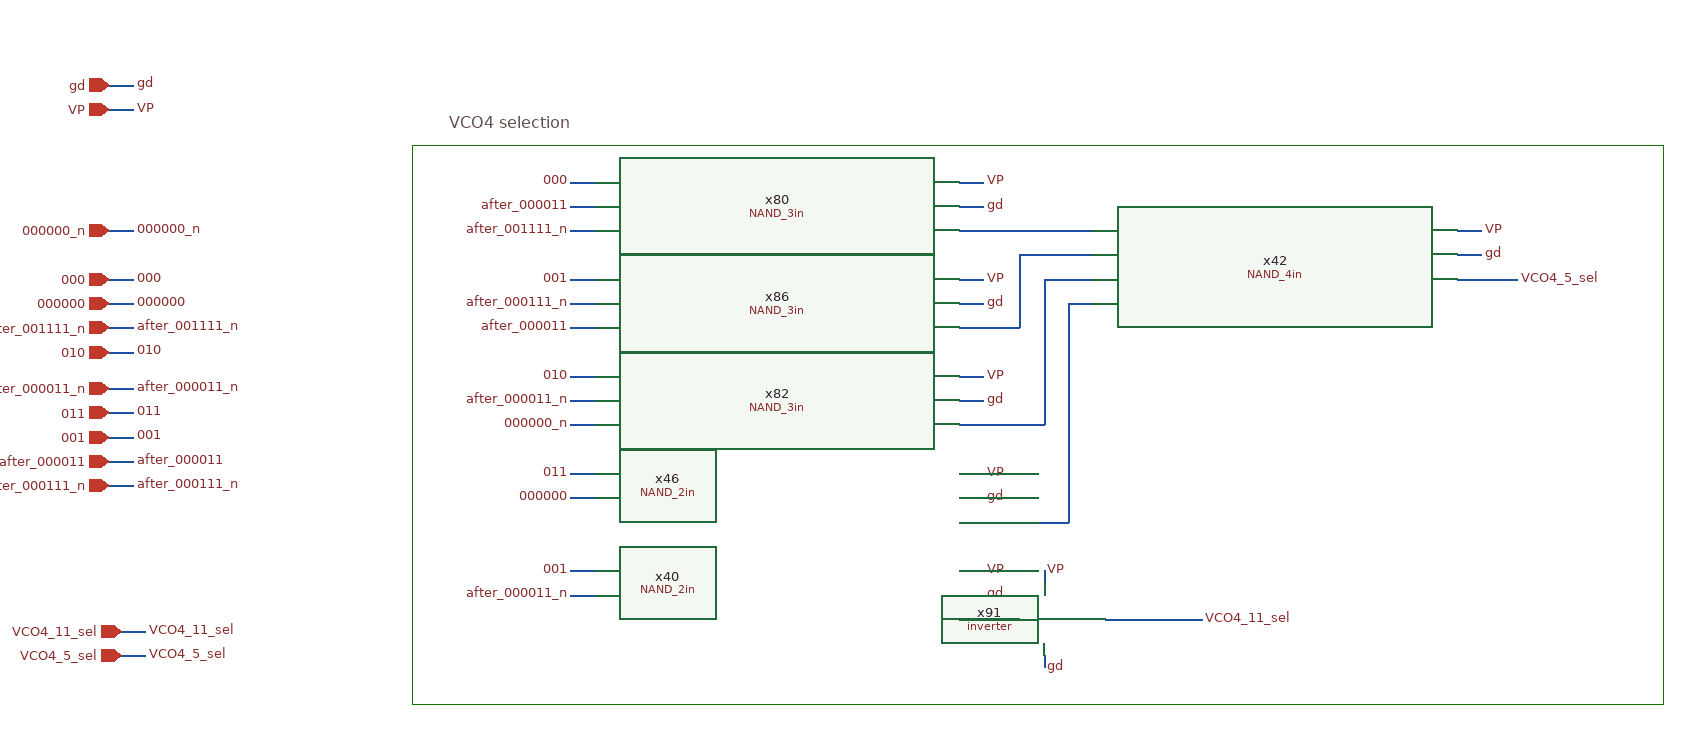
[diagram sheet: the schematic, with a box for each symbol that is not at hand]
v {xschem version=3.4.8RC file_version=1.3}
G {}
K {}
V {}
S {}
F {}
E {}
L 4 2020 -2830 2020 -2490 {}
L 4 2190 -2830 2530 -2830 {}
L 4 2510 -2830 2850 -2830 {}
L 4 2220 -2830 2560 -2830 {}
L 4 2560 -2830 2900 -2830 {}
L 4 2190 -2370 2530 -2370 {}
L 4 2510 -2370 2850 -2370 {}
L 4 3050 -2830 3050 -2490 {}
L 4 2020 -2710 2020 -2370 {}
L 4 2020 -2370 2360 -2370 {}
L 4 2020 -2830 2360 -2830 {}
L 4 3050 -2710 3050 -2370 {}
L 4 2710 -2370 3050 -2370 {}
L 4 2710 -2830 3050 -2830 {}
T {VCO4 selection} 2050 -2860 0 0 0.4 0.4 {}
N 1770 -2880 1790 -2880 {lab=gd}
N 1770 -2860 1790 -2860 {lab=VP}
N 1770 -2760 1790 -2760 {lab=000000_n}
N 1780 -2410 1800 -2410 {lab=VCO4_5_sel}
N 1780 -2430 1800 -2430 {lab=VCO4_11_sel}
N 1770 -2720 1790 -2720 {lab=000}
N 1770 -2700 1790 -2700 {lab=000000}
N 1770 -2680 1790 -2680 {lab=after_001111_n}
N 1770 -2660 1790 -2660 {lab=010}
N 1770 -2630 1790 -2630 {lab=after_000011_n}
N 1770 -2610 1790 -2610 {lab=011}
N 1770 -2590 1790 -2590 {lab=001}
N 1770 -2570 1790 -2570 {lab=after_000011}
N 1770 -2550 1790 -2550 {lab=after_000111_n}
N 2470 -2780 2490 -2780 {lab=gd}
N 2470 -2800 2490 -2800 {lab=VP}
N 2470 -2760 2580 -2760 {lab=#net1}
N 2150 -2800 2170 -2800 {lab=000}
N 2150 -2760 2170 -2760 {lab=after_001111_n}
N 2150 -2780 2170 -2780 {lab=after_000011}
N 2470 -2620 2490 -2620 {lab=gd}
N 2470 -2640 2490 -2640 {lab=VP}
N 2470 -2600 2540 -2600 {lab=#net2}
N 2150 -2640 2170 -2640 {lab=010}
N 2150 -2600 2170 -2600 {lab=000000_n}
N 2150 -2620 2170 -2620 {lab=after_000011_n}
N 2470 -2540 2490 -2540 {lab=gd}
N 2470 -2560 2490 -2560 {lab=VP}
N 2470 -2520 2560 -2520 {lab=#net3}
N 2150 -2560 2170 -2560 {lab=011}
N 2150 -2540 2170 -2540 {lab=000000}
N 2470 -2700 2490 -2700 {lab=gd}
N 2470 -2720 2490 -2720 {lab=VP}
N 2470 -2680 2520 -2680 {lab=#net4}
N 2150 -2720 2170 -2720 {lab=001}
N 2150 -2680 2170 -2680 {lab=after_000011}
N 2470 -2460 2490 -2460 {lab=gd}
N 2470 -2480 2490 -2480 {lab=VP}
N 2540 -2410 2540 -2400 {lab=gd}
N 2540 -2480 2540 -2470 {lab=VP}
N 2470 -2440 2520 -2440 {lab=#net5}
N 2590 -2440 2670 -2440 {lab=VCO4_11_sel}
N 2150 -2480 2170 -2480 {lab=001}
N 2150 -2460 2170 -2460 {lab=after_000011_n}
N 2880 -2740 2900 -2740 {lab=gd}
N 2880 -2760 2900 -2760 {lab=VP}
N 2880 -2720 2930 -2720 {lab=VCO4_5_sel}
N 2150 -2700 2170 -2700 {lab=after_000111_n}
N 2520 -2740 2520 -2680 {lab=#net4}
N 2520 -2740 2580 -2740 {lab=#net4}
N 2540 -2720 2580 -2720 {lab=#net2}
N 2540 -2720 2540 -2600 {lab=#net2}
N 2560 -2700 2560 -2520 {lab=#net3}
N 2560 -2700 2580 -2700 {lab=#net3}
C {iopin.sym} 1770 -2880 2 0 {name=p46 lab=gd}
C {lab_wire.sym} 1790 -2880 2 0 {name=p53 sig_type=std_logic lab=gd}
C {iopin.sym} 1770 -2860 2 0 {name=p54 lab=VP}
C {ipin.sym} 1770 -2760 0 0 {name=p59 lab=000000_n}
C {lab_wire.sym} 1790 -2760 2 0 {name=p60 sig_type=std_logic lab=000000_n}
C {lab_wire.sym} 1790 -2860 2 0 {name=p1 sig_type=std_logic lab=VP}
C {opin.sym} 1780 -2410 0 1 {name=p6 lab=VCO4_5_sel}
C {lab_wire.sym} 1800 -2410 2 0 {name=p7 sig_type=std_logic lab=VCO4_5_sel}
C {opin.sym} 1780 -2430 0 1 {name=p14 lab=VCO4_11_sel}
C {lab_wire.sym} 1800 -2430 2 0 {name=p15 sig_type=std_logic lab=VCO4_11_sel}
C {ipin.sym} 1770 -2720 0 0 {name=p19 lab=000
}
C {lab_wire.sym} 1790 -2720 2 0 {name=p22 sig_type=std_logic lab=000}
C {ipin.sym} 1770 -2700 0 0 {name=p23 lab=000000
}
C {lab_wire.sym} 1790 -2700 2 0 {name=p24 sig_type=std_logic lab=000000}
C {ipin.sym} 1770 -2680 0 0 {name=p25 lab=after_001111_n}
C {lab_wire.sym} 1790 -2680 2 0 {name=p26 sig_type=std_logic lab=after_001111_n}
C {ipin.sym} 1770 -2660 0 0 {name=p27 lab=010}
C {lab_wire.sym} 1790 -2660 2 0 {name=p28 sig_type=std_logic lab=010}
C {ipin.sym} 1770 -2630 0 0 {name=p2 lab=after_000011_n}
C {lab_wire.sym} 1790 -2630 2 0 {name=p3 sig_type=std_logic lab=after_000011_n}
C {ipin.sym} 1770 -2610 0 0 {name=p4 lab=011}
C {lab_wire.sym} 1790 -2610 2 0 {name=p5 sig_type=std_logic lab=011}
C {ipin.sym} 1770 -2590 0 0 {name=p8 lab=001
}
C {lab_wire.sym} 1790 -2590 2 0 {name=p9 sig_type=std_logic lab=001}
C {ipin.sym} 1770 -2570 0 0 {name=p10 lab=after_000011}
C {lab_wire.sym} 1790 -2570 2 0 {name=p11 sig_type=std_logic lab=after_000011}
C {ipin.sym} 1770 -2550 0 0 {name=p12 lab=after_000111_n}
C {lab_wire.sym} 1790 -2550 2 0 {name=p13 sig_type=std_logic lab=after_000111_n}
C {NAND_3in.sym} 2320 -2780 0 0 {name=x80}
C {lab_wire.sym} 2490 -2800 2 0 {name=p327 sig_type=std_logic lab=VP}
C {lab_wire.sym} 2490 -2780 2 0 {name=p328 sig_type=std_logic lab=gd}
C {NAND_3in.sym} 2320 -2620 0 0 {name=x82}
C {lab_wire.sym} 2490 -2640 2 0 {name=p331 sig_type=std_logic lab=VP}
C {lab_wire.sym} 2490 -2620 2 0 {name=p332 sig_type=std_logic lab=gd}
C {lab_wire.sym} 2490 -2560 2 0 {name=p335 sig_type=std_logic lab=VP}
C {lab_wire.sym} 2490 -2540 2 0 {name=p336 sig_type=std_logic lab=gd}
C {NAND_3in.sym} 2320 -2700 0 0 {name=x86}
C {lab_wire.sym} 2490 -2720 2 0 {name=p339 sig_type=std_logic lab=VP}
C {lab_wire.sym} 2490 -2700 2 0 {name=p340 sig_type=std_logic lab=gd}
C {lab_wire.sym} 2490 -2480 2 0 {name=p347 sig_type=std_logic lab=VP}
C {lab_wire.sym} 2490 -2460 2 0 {name=p348 sig_type=std_logic lab=gd}
C {inverter.sym} 2540 -2440 0 0 {name=x91}
C {lab_wire.sym} 2540 -2480 0 1 {name=p349 sig_type=std_logic lab=VP}
C {lab_wire.sym} 2540 -2400 2 0 {name=p350 sig_type=std_logic lab=gd}
C {lab_wire.sym} 2150 -2800 0 0 {name=p357 sig_type=std_logic lab=000}
C {lab_wire.sym} 2150 -2640 0 0 {name=p358 sig_type=std_logic lab=010}
C {lab_wire.sym} 2150 -2560 0 0 {name=p363 sig_type=std_logic lab=011}
C {lab_wire.sym} 2150 -2720 0 0 {name=p364 sig_type=std_logic lab=001}
C {lab_wire.sym} 2670 -2440 2 0 {name=p369 sig_type=std_logic lab=VCO4_11_sel}
C {lab_wire.sym} 2150 -2760 0 0 {name=p371 sig_type=std_logic lab=after_001111_n}
C {lab_wire.sym} 2150 -2780 0 0 {name=p372 sig_type=std_logic lab=after_000011}
C {lab_wire.sym} 2150 -2620 0 0 {name=p373 sig_type=std_logic lab=after_000011_n}
C {lab_wire.sym} 2150 -2480 0 0 {name=p184 sig_type=std_logic lab=001}
C {NAND_2in.sym} 2320 -2460 0 0 {name=x40}
C {lab_wire.sym} 2150 -2460 0 0 {name=p185 sig_type=std_logic lab=after_000011_n}
C {NAND_4in.sym} 2730 -2730 0 0 {name=x42}
C {lab_wire.sym} 2900 -2760 2 0 {name=p186 sig_type=std_logic lab=VP}
C {lab_wire.sym} 2900 -2740 2 0 {name=p187 sig_type=std_logic lab=gd}
C {lab_wire.sym} 2930 -2720 2 0 {name=p188 sig_type=std_logic lab=VCO4_5_sel}
C {lab_wire.sym} 2150 -2680 0 0 {name=p189 sig_type=std_logic lab=after_000011}
C {lab_wire.sym} 2150 -2700 0 0 {name=p190 sig_type=std_logic lab=after_000111_n}
C {NAND_2in.sym} 2320 -2540 0 0 {name=x46}
C {lab_wire.sym} 2150 -2540 0 0 {name=p191 sig_type=std_logic lab=000000}
C {lab_wire.sym} 2150 -2600 0 0 {name=p192 sig_type=std_logic lab=000000_n}
